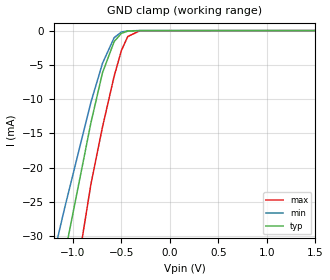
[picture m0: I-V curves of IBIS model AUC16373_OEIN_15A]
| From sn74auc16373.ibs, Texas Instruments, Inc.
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[Model]   AUC16373_OEIN_15A
Model_type  Input
Vinl=0.49
Vinh=1.04
| variable   typ   min   max
C_comp   2.54pF   2.09pF   2.93pF
[Temperature Range]   40   100   -40
| Ambient temperature   25   85   -40
[Voltage range]   1.5   1.4   1.6
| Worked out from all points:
|   GND clamp passes 1 mA (typ) near -0.55 V on its own axis
[GND Clamp]
| AUC16373_OEIN_15A
|   Voltage   I(typ)   I(min)   I(max)
-3.6V     -226.6mA   -190.3mA   -271.8mA
-1.465V   -61.48mA   -49.43mA   -80.77mA
-1.29V    -48.15mA   -38.43mA   -64.9mA
-1.13V    -36.11mA   -28.6mA    -50.37mA
-1.08V    -32.4mA    -25.59mA   -45.83mA
-815mV    -13.48mA   -10.49mA   -22.45mA
-695mV    -6.152mA   -4.773mA   -14.06mA
-575mV    -1.605mA   -1.034mA   -6.664mA
-500mV    -407.2uA   -207.5uA   -2.896mA
-435mV    -83.64uA   -40.42uA   -873uA
-310mV    -2.072uA   -1.331uA   -17.49uA
1.5V      165.9pA    259.7pA    172.1pA
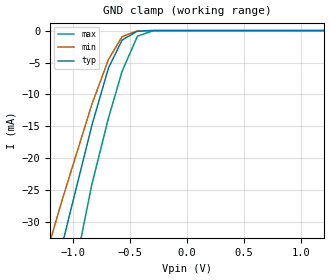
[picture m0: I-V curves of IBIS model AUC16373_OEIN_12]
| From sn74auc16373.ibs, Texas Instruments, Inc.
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[Model]   AUC16373_OEIN_12
Model_type  Input
Vinl=0.385
Vinh=0.845
| variable   typ   min   max
C_comp   2.58pF   2.18pF   2.94pF
[Temperature Range]   40   100   -40
| Ambient temperature   25   85   -40
[Voltage range]   1.2   1.1   1.3
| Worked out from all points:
|   GND clamp passes 1 mA (typ) near -0.55 V on its own axis
[GND Clamp]
| AUC16373_OEIN_12
|   Voltage   I(typ)   I(min)   I(max)
-3.6V     -226.6mA   -190.3mA   -271.8mA
-1.47V    -61.86mA   -49.74mA   -81.22mA
-1.425V   -58.42mA   -46.89mA   -77.15mA
-1.295V   -48.52mA   -38.74mA   -65.35mA
-1.13V    -36.11mA   -28.6mA    -50.37mA
-1.09V    -33.13mA   -26.19mA   -46.74mA
-835mV    -14.83mA   -11.55mA   -24.08mA
-690mV    -5.892mA   -4.567mA   -13.74mA
-570mV    -1.488mA   -943.5uA   -6.381mA
-435mV    -83.64uA   -40.42uA   -873uA
-295mV    -1.276uA   -867.5nA   -9.761uA
1.2V      133.3pA    224.2pA    123.7pA
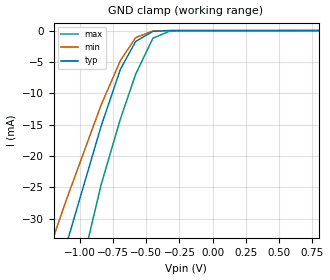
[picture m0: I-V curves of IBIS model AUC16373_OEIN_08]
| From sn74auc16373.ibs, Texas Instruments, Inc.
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[Model]   AUC16373_OEIN_08
Model_type  Input
Vinl=0
Vinh=0.8
| variable   typ   min   max
C_comp   2.61pF   2.27pF   2.93pF
[Temperature Range]   40   100   -40
| Ambient temperature   25   85   -40
[Voltage range]   0.8   0.8   0.8
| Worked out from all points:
|   GND clamp passes 1 mA (typ) near -0.55 V on its own axis
[GND Clamp]
| AUC16373_OEIN_08
|   Voltage   I(typ)   I(min)   I(max)
-3.6V     -226.6mA   -190.3mA   -271.8mA
-1.485V   -63.01mA   -50.7mA    -82.58mA
-1.445V   -59.95mA   -48.16mA   -78.96mA
-1.305V   -49.28mA   -39.36mA   -66.26mA
-1.135V   -36.48mA   -28.9mA    -50.82mA
-1.1V     -33.88mA   -26.79mA   -47.64mA
-840mV    -15.17mA   -11.81mA   -24.5mA
-695mV    -6.152mA   -4.773mA   -14.06mA
-580mV    -1.726mA   -1.13mA    -6.949mA
-450mV    -123.7uA   -59.61uA   -1.212mA
-315mV    -2.431uA   -1.534uA   -21.15uA
800mV     96.17pA    180.2pA    76.88pA
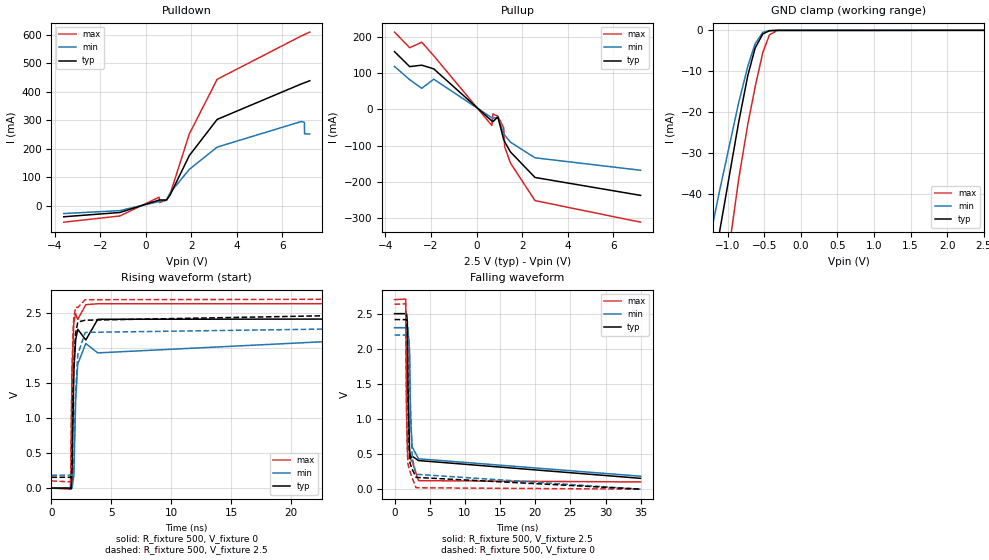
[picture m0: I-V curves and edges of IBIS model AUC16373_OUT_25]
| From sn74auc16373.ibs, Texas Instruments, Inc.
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[Model]   AUC16373_OUT_25
Model_type  3-state
Enable   Active-Low
Vref =   0
Rref =   500
Cref =   30p
Vmeas =   1.25
| variable   typ   min   max
C_comp   5.25pF   4.69pF   5.48pF
| C_pullup   7.79pF   4.63pF   11.98pF
| C_pulldown   6.70pF   4.68pF   15.30pF
| C_tri-state   5.25pF   4.69pF   5.48pF
[Temperature Range]   40   100   -40
| Ambient temperature   25   85   -40
[Voltage range]   2.5   2.3   2.7
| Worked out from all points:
|   slope of the pulldown table from 0 to 0.375 V, typ, clamps not added: 30.7 ohm
|   slope of the pullup table from 0 to 0.375 V, typ, clamps not added: 19 ohm
|   GND clamp passes 1 mA (typ) near -0.53 V on its own axis
|   rising waveform, R_fixture 500, V_fixture 0: 20-80 % time 198ps typ, 278ps min, 143ps max; typ from 0 V to 2.42 V
|   falling waveform, R_fixture 500, V_fixture 2.5: 20-80 % time 246ps typ, 345ps min, 178ps max; typ from 2.5 V to 0.154 V
|   rising waveform, R_fixture 500, V_fixture 2.5: 20-80 % time 201ps typ, 284ps min, 143ps max; typ from 0.154 V to 2.5 V
|   falling waveform, R_fixture 500, V_fixture 0: 20-80 % time 266ps typ, 378ps min, 182ps max; typ from 2.42 V to 0 V
[GND Clamp]
| AUC16373_OUT_25
|   Voltage   I(typ)   I(min)   I(max)
-3.6V     -322.9mA   -271.3mA   -392.8mA
-1.455V   -86.41mA   -69.74mA   -115.3mA
-1.345V   -74.46mA   -59.86mA   -100.9mA
-1.295V   -69.05mA   -55.41mA   -94.31mA
-1.105V   -48.71mA   -38.79mA   -69.37mA
-850mV    -22.51mA   -17.75mA   -36.48mA
-725mV    -11.06mA   -8.768mA   -23.02mA
-625mV    -4.339mA   -3.267mA   -13.84mA
-520mV    -878.8uA   -491uA     -5.429mA
-430mV    -104.5uA   -60.64uA   -1.111mA
-325mV    -4.915uA   -5.536uA   -43.94uA
2.5V      1.045nA    211.8nA    1.502nA
[Pulldown]
| AUC16373_OUT_25
|   Voltage   I(typ)   I(min)   I(max)
-3.6V     -38.75mA   -27.46mA   -57.79mA
-1.14V    -23.79mA   -17.18mA   -36mA
590mV     19.92mA    14.98mA    30.03mA
600mV     20.28mA    15.25mA    11.17mA
910mV     20.16mA    20.33mA    19.24mA
1.07V     37.88mA    45.66mA    41.07mA
1.915V    176.4mA    127.8mA    252.5mA
3.135V    303.2mA    205.9mA    444mA
6.825V    427.7mA    295.8mA    596.2mA
6.965V    431.9mA    293mA      601.3mA
6.97V     432.1mA    252.7mA    601.5mA
7.2V      439mA      251.9mA    609.9mA
[Pullup]
| AUC16373_OUT_25
|   Voltage   I(typ)   I(min)   I(max)
-3.6V     160mA      119mA      214.2mA
-2.935V   118.6mA    82.49mA    170.9mA
-2.405V   122.6mA    58.64mA    186.2mA
-1.88V    112.5mA    83.79mA    148.8mA
670mV     -31.69mA   -22.93mA   -44.2mA
720mV     -33.47mA   -24.18mA   -12.23mA
935mV     -20.74mA   -21.43mA   -18.64mA
1.19V     -83.17mA   -67.47mA   -51.41mA
1.235V    -89.46mA   -71.21mA   -103.5mA
1.49V     -117.6mA   -90.51mA   -148.5mA
2.565V    -188.1mA   -133.7mA   -252.1mA
7.2V      -237.7mA   -168.2mA   -311.9mA
[Ramp]
| AUC16373_OUT_25
| variable   typ   min   max
dV/dt_r   1.46/1.99E-10   1.33/2.81E-10   1.59/1.45E-10
dV/dt_f   1.41/2.48E-10   1.27/3.47E-10   1.56/1.79E-10
R_load = 500
[Rising Waveform]
| AUC16373_OUT_25
R_fixture =   500
C_fixture =   0
L_fixture =   0
V_fixture =   0
V_fixture_min = 0
V_fixture_max = 0
|   Time   V(typ)   V(min)   V(max)
0s        12.33nV    36.82nV    2.005nV
1.585ns   -465.6uV   686.3uV    -15.47mV
1.635ns   -12.82mV   864.7uV    242.2mV
1.715ns   136.4mV    -5.862mV   1.619V
1.875ns   1.678V     178.2mV    2.364V
2.025ns   2.118V     1.253V     2.49V
2.2ns     2.268V     1.772V     2.409V
2.87ns    2.116V     2.065V     2.62V
3.87ns    2.411V     1.931V     2.633V
34.99ns   2.416V     2.195V     2.634V
[Falling Waveform]
| AUC16373_OUT_25
R_fixture =   500
C_fixture =   0
L_fixture =   0
V_fixture =   2.5
V_fixture_min = 2.3
V_fixture_max = 2.7
|   Time   V(typ)   V(min)   V(max)
0s        2.5V       2.3V       2.7V
1.585ns   2.5V       2.3V       2.708V
1.715ns   2.498V     2.3V       1.101V
1.82ns    2.391V     2.299V     644.1mV
1.905ns   1.439V     2.298V     432mV
2.135ns   572.3mV    1.975V     439.6mV
2.275ns   438.4mV    1.042V     426.9mV
2.495ns   469.6mV    605.1mV    396.2mV
3.405ns   407.7mV    433mV      121mV
34.99ns   154.5mV    184.4mV    102.7mV
[Rising Waveform]
| AUC16373_OUT_25
R_fixture =   500
C_fixture =   0
L_fixture =   0
V_fixture =   2.5
V_fixture_min = 2.3
V_fixture_max = 2.7
|   Time   V(typ)   V(min)   V(max)
0s        154.5mV    184.4mV    102.6mV
1.585ns   154.2mV    185mV      88.67mV
1.63ns    144.9mV    185.2mV    300.5mV
1.705ns   261.9mV    181.8mV    1.588V
1.81ns    1.379V     206.7mV    2.255V
1.87ns    1.74V      394.7mV    2.437V
2.02ns    2.212V     1.372V     2.584V
2.205ns   2.372V     1.91V      2.58V
2.825ns   2.398V     2.224V     2.691V
34.99ns   2.5V       2.3V       2.7V
[Falling Waveform]
| AUC16373_OUT_25
R_fixture =   500
C_fixture =   0
L_fixture =   0
V_fixture =   0
V_fixture_min = 0
V_fixture_max = 0
|   Time   V(typ)   V(min)   V(max)
0s        2.416V     2.195V     2.634V
1.585ns   2.415V     2.195V     2.64V
1.71ns    2.413V     2.195V     1.095V
1.82ns    2.295V     2.194V     565.5mV
1.89ns    1.522V     2.193V     367.9mV
2.075ns   596.8mV    2.11V      294mV
2.2ns     369.3mV    1.33V      253.3mV
2.525ns   281.2mV    437.4mV    155.7mV
3.07ns    167.6mV    211.8mV    20.01mV
34.99ns   28.01uV    546.6nV    12.98uV
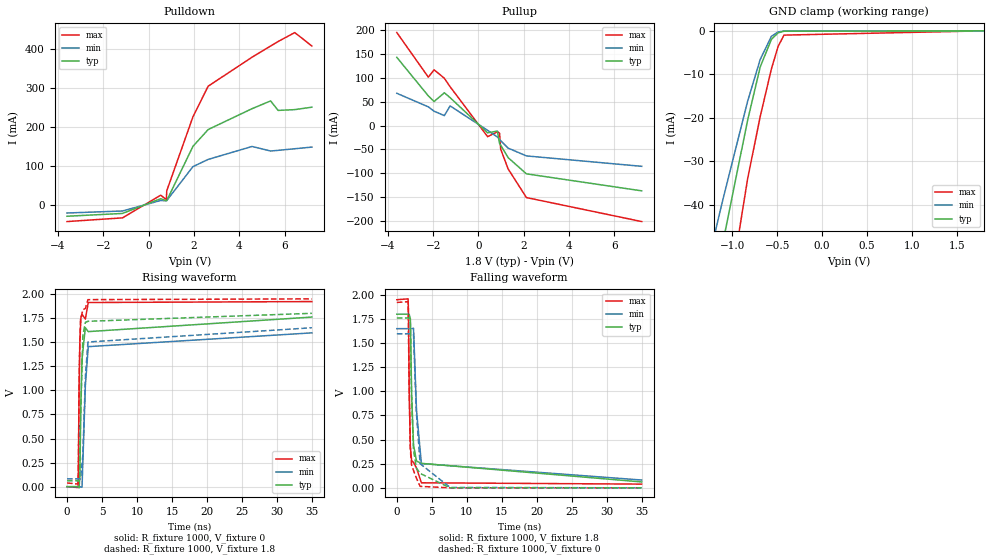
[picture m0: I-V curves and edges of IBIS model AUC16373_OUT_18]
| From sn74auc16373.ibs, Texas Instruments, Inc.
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[Model]   AUC16373_OUT_18
Model_type  3-state
Enable   Active-Low
Vref =   0
Rref =   1000
Cref =   30p
Vmeas =   0.9
| variable   typ   min   max
C_comp   5.46pF   4.89pF   5.67pF
| C_pullup   6.29pF   0.99pF   11.78pF
| C_pulldown   6.09pF   1.85pF   13.80pF
| C_tri-state   5.46pF   4.89pF   5.67pF
[Temperature Range]   40   100   -40
| Ambient temperature   25   85   -40
[Voltage range]   1.8   1.65   1.95
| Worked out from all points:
|   slope of the pulldown table from 0 to 0.27 V, typ, clamps not added: 34.2 ohm
|   slope of the pullup table from 0 to 0.27 V, typ, clamps not added: 24.9 ohm
|   GND clamp passes 1 mA (typ) near -0.53 V on its own axis
|   rising waveform, R_fixture 1000, V_fixture 0: 20-80 % time 306ps typ, 479ps min, 198ps max; typ from 0 V to 1.76 V
|   falling waveform, R_fixture 1000, V_fixture 1.8: 20-80 % time 400ps typ, 627ps min, 239ps max; typ from 1.8 V to 0.061 V
|   rising waveform, R_fixture 1000, V_fixture 1.8: 20-80 % time 304ps typ, 475ps min, 196ps max; typ from 0.061 V to 1.8 V
|   falling waveform, R_fixture 1000, V_fixture 0: 20-80 % time 401ps typ, 630ps min, 238ps max; typ from 1.76 V to 0 V
[GND Clamp]
| AUC16373_OUT_18
|   Voltage   I(typ)   I(min)   I(max)
-3.6V     -322.9mA   -271.3mA   -392.8mA
-1.48V    -89.14mA   -71.99mA   -118.6mA
-1.435V   -84.24mA   -67.93mA   -112.7mA
-1.3V     -69.59mA   -55.85mA   -94.97mA
-1.15V    -53.49mA   -42.68mA   -75.27mA
-1.1V     -48.18mA   -38.36mA   -68.71mA
-830mV    -20.57mA   -16.22mA   -34.06mA
-690mV    -8.335mA   -6.605mA   -19.75mA
-565mV    -1.951mA   -1.255mA   -8.764mA
-490mV    -463.9uA   -245.9uA   -3.576mA
-425mV    -91.38uA   -54.15uA   -985.3uA
1.8V      674.7pA    45.17nA    747.9pA
[Pulldown]
| AUC16373_OUT_18
|   Voltage   I(typ)   I(min)   I(max)
-3.6V     -28.49mA   -20.22mA   -42.08mA
-1.155V   -21.32mA   -15.05mA   -32.66mA
530mV     16.28mA    11.83mA    25.26mA
780mV     11.06mA    10.81mA    14.1mA
800mV     11.7mA     11.72mA    36.72mA
1.955V    150.3mA    98.42mA    225.9mA
2.625V    193.2mA    116.8mA    304mA
4.56V     246.5mA    149.9mA    378.1mA
5.38V     266.4mA    138.3mA    406.9mA
5.71V     242.1mA    140mA      418.2mA
6.445V    244.1mA    144.1mA    441.1mA
7.2V      250.4mA    148.3mA    406.7mA
[Pullup]
| AUC16373_OUT_18
|   Voltage   I(typ)   I(min)   I(max)
-3.6V     143.4mA    67.81mA    195.5mA
-2.21V    62.22mA    39.25mA    101.7mA
-1.955V   50.53mA    30.07mA    117.2mA
-1.505V   68.89mA    20.87mA    99.46mA
-1.25V    58.62mA    41.27mA    81.57mA
405mV     -15.38mA   -10.2mA    -23.47mA
835mV     -11.64mA   -24.19mA   -13.09mA
930mV     -37.45mA   -29.05mA   -16.21mA
980mV     -41.44mA   -31.73mA   -49.64mA
1.31V     -67.6mA    -47.58mA   -91.39mA
2.115V    -101.6mA   -63.91mA   -151.5mA
7.2V      -137.4mA   -85.82mA   -202mA
[Ramp]
| AUC16373_OUT_18
| variable   typ   min   max
dV/dt_r   1.07/3.10E-10   0.97/4.87E-10   1.16/1.99E-10
dV/dt_f   1.05/4.02E-10   0.95/6.30E-10   1.15/2.41E-10
R_load = 1000
[Rising Waveform]
| AUC16373_OUT_18
R_fixture =   1000
C_fixture =   0
L_fixture =   0
V_fixture =   0
V_fixture_min = 0
V_fixture_max = 0
|   Time   V(typ)   V(min)   V(max)
0s        9.675nV    33.63nV    1.209nV
1.575ns   554.8uV    24.29uV    -9.009mV
1.62ns    796.3uV    56.73uV    113.6mV
1.725ns   -12.08mV   182.5uV    1.018V
1.835ns   108mV      1.353mV    1.498V
1.98ns    865.2mV    -5.302mV   1.752V
2.145ns   1.329V     -3.297mV   1.79V
2.62ns    1.651V     1.049V     1.74V
3.035ns   1.61V      1.454V     1.912V
34.99ns   1.761V     1.597V     1.922V
[Falling Waveform]
| AUC16373_OUT_18
R_fixture =   1000
C_fixture =   0
L_fixture =   0
V_fixture =   1.8
V_fixture_min = 1.65
V_fixture_max = 1.95
|   Time   V(typ)   V(min)   V(max)
0s        1.8V       1.65V      1.95V
1.61ns    1.8V       1.65V      1.959V
1.665ns   1.8V       1.65V      1.838V
1.77ns    1.798V     1.65V      1.003V
1.935ns   1.752V     1.65V      423.6mV
2.115ns   962.5mV    1.65V      281.6mV
2.385ns   443.9mV    1.655V     264.3mV
2.815ns   278.2mV    798.9mV    204.5mV
3.51ns    253.9mV    251.7mV    52.38mV
34.99ns   61.08mV    81.02mV    38.7mV
[Rising Waveform]
| AUC16373_OUT_18
R_fixture =   1000
C_fixture =   0
L_fixture =   0
V_fixture =   1.8
V_fixture_min = 1.65
V_fixture_max = 1.95
|   Time   V(typ)   V(min)   V(max)
0s        61.05mV    81.01mV    38.68mV
1.57ns    61.53mV    81.03mV    27.73mV
1.62ns    61.82mV    81.06mV    167.1mV
1.705ns   54.68mV    81.13mV    929.6mV
1.8ns     84.7mV     81.83mV    1.417V
1.925ns   686.5mV    80.95mV    1.734V
2.27ns    1.574V     336.2mV    1.837V
2.625ns   1.706V     1.144V     1.85V
2.99ns    1.717V     1.502V     1.942V
34.99ns   1.8V       1.65V      1.95V
[Falling Waveform]
| AUC16373_OUT_18
R_fixture =   1000
C_fixture =   0
L_fixture =   0
V_fixture =   0
V_fixture_min = 0
V_fixture_max = 0
|   Time   V(typ)   V(min)   V(max)
0s        1.761V     1.597V     1.922V
1.61ns    1.761V     1.597V     1.93V
1.765ns   1.759V     1.597V     1.008V
1.93ns    1.716V     1.597V     395.4mV
2.1ns     974.7mV    1.597V     236.6mV
2.38ns    393.7mV    1.596V     181mV
2.8ns     204.6mV    768.9mV    100.5mV
3.33ns    149.6mV    250mV      15.44mV
7.615ns   329.2uV    4.425mV    113.2uV
34.99ns   34.64uV    2.32uV     14.99uV
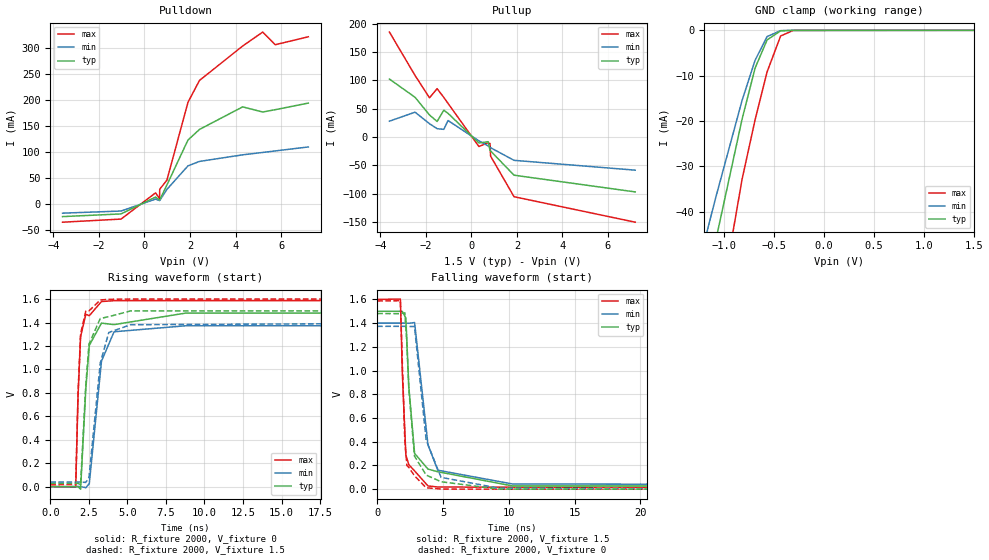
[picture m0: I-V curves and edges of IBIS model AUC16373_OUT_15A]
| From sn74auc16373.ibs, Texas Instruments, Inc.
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[Model]   AUC16373_OUT_15A
Model_type  3-state
Enable   Active-Low
Vref =   0
Rref =   2000
Cref =   15p
Vmeas =   0.75
| variable   typ   min   max
C_comp   5.56pF   5.00pF   5.81pF
| C_pullup   4.92pF   0.36pF   12.47pF
| C_pulldown   6.29pF   5.37pF   9.88pF
| C_tri-state   5.56pF   5.00pF   5.81pF
[Temperature Range]   40   100   -40
| Ambient temperature   25   85   -40
[Voltage range]   1.5   1.4   1.6
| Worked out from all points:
|   slope of the pulldown table from 0 to 0.225 V, typ, clamps not added: 37.2 ohm
|   slope of the pullup table from 0 to 0.225 V, typ, clamps not added: 30 ohm
|   GND clamp passes 1 mA (typ) near -0.53 V on its own axis
|   rising waveform, R_fixture 2000, V_fixture 0: 20-80 % time 406ps typ, 638ps min, 248ps max; typ from 0 V to 1.48 V
|   falling waveform, R_fixture 2000, V_fixture 1.5: 20-80 % time 546ps typ, 882ps min, 307ps max; typ from 1.5 V to 0.027 V
|   rising waveform, R_fixture 2000, V_fixture 1.5: 20-80 % time 402ps typ, 633ps min, 245ps max; typ from 0.027 V to 1.5 V
|   falling waveform, R_fixture 2000, V_fixture 0: 20-80 % time 542ps typ, 875ps min, 304ps max; typ from 1.48 V to 0 V
[GND Clamp]
| AUC16373_OUT_15A
|   Voltage   I(typ)   I(min)   I(max)
-3.6V     -322.9mA   -271.3mA   -392.8mA
-1.475V   -88.59mA   -71.54mA   -117.9mA
-1.34V    -73.92mA   -59.41mA   -100.2mA
-1.3V     -69.59mA   -55.85mA   -94.97mA
-1.135V   -51.9mA    -41.38mA   -73.31mA
-1.085V   -46.6mA    -37.08mA   -66.75mA
-820mV    -19.61mA   -15.47mA   -32.88mA
-690mV    -8.335mA   -6.605mA   -19.75mA
-570mV    -2.107mA   -1.378mA   -9.166mA
-435mV    -119.4uA   -67.96uA   -1.249mA
-310mV    -3.104uA   -3.774uA   -25uA
1.5V      550.3pA    9.378nA    545.2pA
[Pulldown]
| AUC16373_OUT_15A
|   Voltage   I(typ)   I(min)   I(max)
-3.6V     -23.87mA   -17.26mA   -34.61mA
-1.03V    -18.71mA   -13.15mA   -28.63mA
485mV     13.68mA    9.737mA    21.72mA
660mV     8.179mA    6.953mA    10.96mA
670mV     8.319mA    7.1mA      28.79mA
985mV     36.88mA    28.41mA    46.12mA
1.91V     123.2mA    73.57mA    195.6mA
2.415V    143.6mA    82.17mA    237.7mA
4.315V    187mA      94.84mA    304mA
5.195V    177.1mA    99.4mA     330.7mA
5.745V    181.6mA    102.3mA    306.4mA
7.2V      194.3mA    110mA      321.7mA
[Pullup]
| AUC16373_OUT_15A
|   Voltage   I(typ)   I(min)   I(max)
-3.6V     102.1mA    27.92mA    184.9mA
-2.475V   70.01mA    43.77mA    108.5mA
-1.84V    38.84mA    23.47mA    69.11mA
-1.505V   27.39mA    14.66mA    85.19mA
-1.21V    47.39mA    13.5mA     69.72mA
-1.025V   41.71mA    29.01mA    59.25mA
330mV     -10.46mA   -6.758mA   -16.68mA
740mV     -8.272mA   -15.76mA   -10.25mA
820mV     -23.65mA   -18mA      -11.49mA
845mV     -24.61mA   -18.86mA   -33.67mA
1.875V    -67.28mA   -41.09mA   -105.2mA
7.2V      -96.75mA   -58.41mA   -150.1mA
[Ramp]
| AUC16373_OUT_15A
| variable   typ   min   max
dV/dt_r   0.90/4.08E-10   0.83/6.50E-10   0.96/2.49E-10
dV/dt_f   0.89/5.49E-10   0.82/8.93E-10   0.95/3.07E-10
R_load = 2000
[Rising Waveform]
| AUC16373_OUT_15A
R_fixture =   2000
C_fixture =   0
L_fixture =   0
V_fixture =   0
V_fixture_min = 0
V_fixture_max = 0
|   Time   V(typ)   V(min)   V(max)
0s        8.895nV    33.88nV    950.2pV
1.65ns    8.033uV    38.9uV     -4.678mV
1.8ns     373.4uV    261.9uV    773.5mV
1.965ns   -21.9mV    621.6uV    1.279V
2.305ns   834.7mV    -9.422mV   1.47V
2.53ns    1.205V     25.26mV    1.458V
3.32ns    1.395V     1.07V      1.579V
4.135ns   1.382V     1.321V     1.586V
8.765ns   1.48V      1.372V     1.587V
34.99ns   1.481V     1.373V     1.587V
[Falling Waveform]
| AUC16373_OUT_15A
R_fixture =   2000
C_fixture =   0
L_fixture =   0
V_fixture =   1.5
V_fixture_min = 1.4
V_fixture_max = 1.6
|   Time   V(typ)   V(min)   V(max)
0s        1.5V       1.4V       1.6V
1.765ns   1.5V       1.4V       1.603V
1.91ns    1.499V     1.4V       988.1mV
2.18ns    1.444V     1.4V       289mV
2.405ns   863.5mV    1.399V     206.4mV
2.845ns   301.2mV    1.405V     154mV
3.86ns    169.3mV    374.8mV    27.48mV
4.605ns   147mV      160mV      18.27mV
10.27ns   27.45mV    44.07mV    16.49mV
34.99ns   27.21mV    38.76mV    16.42mV
[Rising Waveform]
| AUC16373_OUT_15A
R_fixture =   2000
C_fixture =   0
L_fixture =   0
V_fixture =   1.5
V_fixture_min = 1.4
V_fixture_max = 1.6
|   Time   V(typ)   V(min)   V(max)
0s        27.17mV    38.75mV    16.4mV
1.65ns    27.18mV    38.79mV    17.02mV
1.8ns     27.59mV    38.98mV    799.5mV
1.965ns   14.56mV    39.28mV    1.302V
2.3ns     861.5mV    35.58mV    1.496V
2.51ns    1.216V     78.12mV    1.499V
3.24ns    1.434V     1.054V     1.592V
3.795ns   1.45V      1.315V     1.598V
5.21ns    1.499V     1.381V     1.6V
34.99ns   1.5V       1.4V       1.6V
[Falling Waveform]
| AUC16373_OUT_15A
R_fixture =   2000
C_fixture =   0
L_fixture =   0
V_fixture =   0
V_fixture_min = 0
V_fixture_max = 0
|   Time   V(typ)   V(min)   V(max)
0s        1.481V     1.373V     1.587V
1.765ns   1.48V      1.373V     1.589V
2.1ns     1.487V     1.373V     414.7mV
2.255ns   1.242V     1.372V     201.1mV
2.41ns    837.6mV    1.371V     182.5mV
2.835ns   278.8mV    1.372V     113.4mV
3.725ns   118.7mV    412.9mV    11.7mV
4.855ns   62.72mV    99.58mV    1.01mV
9.25ns    318.7uV    8.392mV    103uV
34.99ns   39.77uV    4.299uV    16.51uV
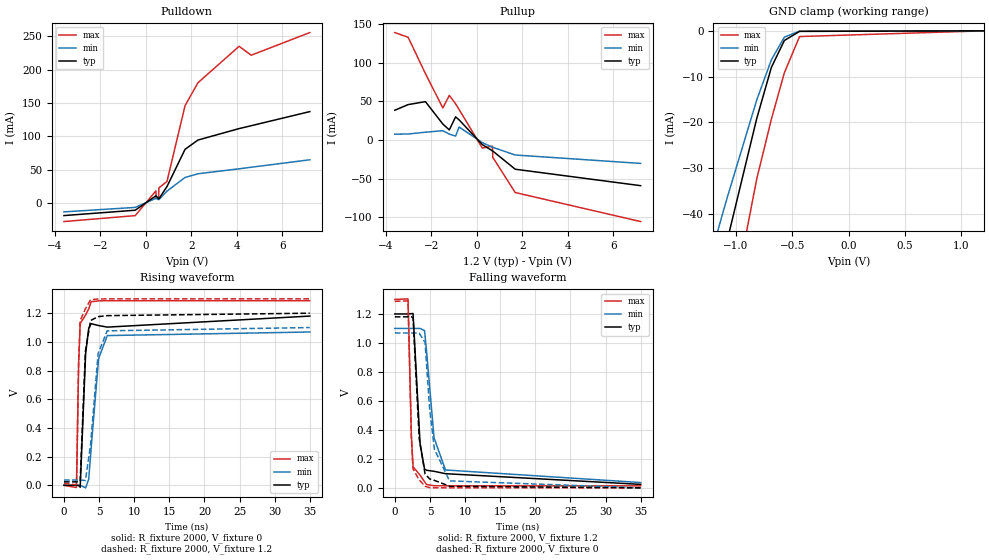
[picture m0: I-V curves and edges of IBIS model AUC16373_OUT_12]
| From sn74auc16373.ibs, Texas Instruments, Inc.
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[Model]   AUC16373_OUT_12
Model_type  3-state
Enable   Active-Low
Vref =   0
Rref =   2000
Cref =   15p
Vmeas =   0.6
| variable   typ   min   max
C_comp   5.67pF   5.13pF   5.90pF
| C_pullup   4.94pF   0.61pF   9.78pF
| C_pulldown   6.25pF   5.49pF   7.45pF
| C_tri-state   5.67pF   5.13pF   5.90pF
[Temperature Range]   40   100   -40
| Ambient temperature   25   85   -40
[Voltage range]   1.2   1.1   1.3
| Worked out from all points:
|   slope of the pulldown table from 0 to 0.18 V, typ, clamps not added: 42.1 ohm
|   slope of the pullup table from 0 to 0.18 V, typ, clamps not added: 38.3 ohm
|   GND clamp passes 1 mA (typ) near -0.53 V on its own axis
|   rising waveform, R_fixture 2000, V_fixture 0: 20-80 % time 583ps typ, 1.04ns min, 320ps max; typ from 0 V to 1.18 V
|   falling waveform, R_fixture 2000, V_fixture 1.2: 20-80 % time 855ps typ, 1.39ns min, 422ps max; typ from 1.2 V to 0.024 V
|   rising waveform, R_fixture 2000, V_fixture 1.2: 20-80 % time 575ps typ, 1.03ns min, 314ps max; typ from 0.024 V to 1.2 V
|   falling waveform, R_fixture 2000, V_fixture 0: 20-80 % time 842ps typ, 1.32ns min, 416ps max; typ from 1.18 V to 0 V
[GND Clamp]
| AUC16373_OUT_12
|   Voltage   I(typ)   I(min)   I(max)
-3.6V     -322.9mA   -271.3mA   -392.8mA
-1.47V    -88.05mA   -71.09mA   -117.3mA
-1.425V   -83.15mA   -67.03mA   -111.4mA
-1.3V     -69.59mA   -55.85mA   -94.97mA
-1.26V    -65.27mA   -52.31mA   -89.72mA
-1.11V    -49.24mA   -39.22mA   -70.03mA
-1.075V   -45.55mA   -36.22mA   -65.44mA
-815mV    -19.13mA   -15.09mA   -32.31mA
-685mV    -7.975mA   -6.314mA   -19.28mA
-570mV    -2.107mA   -1.378mA   -9.166mA
-435mV    -119.4uA   -67.96uA   -1.249mA
1.2V      442.5pA    9.259nA    389.9pA
[Pulldown]
| AUC16373_OUT_12
|   Voltage   I(typ)   I(min)   I(max)
-3.6V     -19.18mA   -13.63mA   -28.17mA
-470mV    -11.13mA   -6.91mA    -19.23mA
440mV     10.48mA    6.706mA    17.92mA
445mV     10.59mA    6.769mA    6.318mA
560mV     5.857mA    4.698mA    8.209mA
570mV     5.97mA     4.786mA    22.41mA
925mV     24.38mA    17.54mA    32.09mA
1.72V     80.36mA    38.11mA    146mA
2.285V    94.25mA    43.63mA    180.3mA
4.095V    111.5mA    51.07mA    235.1mA
4.625V    115.8mA    53.41mA    221.7mA
7.2V      137mA      64.62mA    255.7mA
[Pullup]
| AUC16373_OUT_12
|   Voltage   I(typ)   I(min)   I(max)
-3.6V     38.61mA    7.555mA    139.2mA
-3.015V   45.91mA    7.851mA    133.1mA
-2.255V   49.73mA    10.14mA    86.01mA
-1.49V    20.68mA    12.09mA    41.55mA
-1.205V   13.08mA    7.704mA    57.86mA
-930mV    30.05mA    5.088mA    46.93mA
-775mV    26.1mA     16.83mA    39.5mA
245mV     -5.916mA   -3.381mA   -10.43mA
690mV     -14.05mA   -9.319mA   -7.997mA
705mV     -14.25mA   -9.473mA   -22.45mA
1.69V     -37.81mA   -19.38mA   -68.01mA
7.2V      -59.11mA   -30.28mA   -105.6mA
[Ramp]
| AUC16373_OUT_12
| variable   typ   min   max
dV/dt_r   0.72/5.96E-10   0.65/1.06E-09   0.78/3.23E-10
dV/dt_f   0.71/8.67E-10   0.64/1.43E-09   0.77/4.24E-10
R_load = 2000
[Rising Waveform]
| AUC16373_OUT_12
R_fixture =   2000
C_fixture =   0
L_fixture =   0
V_fixture =   0
V_fixture_min = 0
V_fixture_max = 0
|   Time   V(typ)   V(min)   V(max)
0s        8.336nV    36nV       765.5pV
1.77ns    140.6uV    -1.439uV   -15.28mV
2.085ns   -1.371mV   128.8uV    841.3mV
2.305ns   -13.39mV   301.3uV    1.128V
3.08ns    919.1mV    -17.75mV   1.188V
3.52ns    1.094V     42.93mV    1.229V
3.865ns   1.127V     258.3mV    1.28V
4.925ns   1.114V     883.6mV    1.286V
6.17ns    1.103V     1.044V     1.287V
34.99ns   1.18V      1.069V     1.287V
[Falling Waveform]
| AUC16373_OUT_12
R_fixture =   2000
C_fixture =   0
L_fixture =   0
V_fixture =   1.2
V_fixture_min = 1.1
V_fixture_max = 1.3
|   Time   V(typ)   V(min)   V(max)
0s        1.2V       1.1V       1.3V
1.88ns    1.2V       1.1V       1.304V
2.355ns   1.202V     1.1V       366.1mV
2.595ns   1.203V     1.1V       145.6mV
3.595ns   304.3mV    1.1V       87.5mV
4.23ns    129.6mV    1.085V     42.1mV
4.52ns    121.3mV    941.7mV    23.25mV
5.585ns   114.2mV    345.2mV    14.69mV
7.21ns    97.74mV    123.4mV    14.05mV
34.99ns   24.03mV    36.64mV    13.88mV
[Rising Waveform]
| AUC16373_OUT_12
R_fixture =   2000
C_fixture =   0
L_fixture =   0
V_fixture =   1.2
V_fixture_min = 1.1
V_fixture_max = 1.3
|   Time   V(typ)   V(min)   V(max)
0s        23.98mV    36.61mV    13.86mV
1.77ns    24.1mV     36.61mV    3.599mV
1.82ns    24.16mV    36.61mV    72.51mV
2.08ns    23.65mV    36.68mV    859.5mV
2.305ns   26.1mV     36.78mV    1.149V
3.05ns    935.8mV    32.98mV    1.23V
3.78ns    1.149V     281.1mV    1.294V
4.855ns   1.176V     918.2mV    1.299V
6.15ns    1.183V     1.077V     1.3V
34.99ns   1.2V       1.1V       1.3V
[Falling Waveform]
| AUC16373_OUT_12
R_fixture =   2000
C_fixture =   0
L_fixture =   0
V_fixture =   0
V_fixture_min = 0
V_fixture_max = 0
|   Time   V(typ)   V(min)   V(max)
0s        1.18V      1.069V     1.287V
1.88ns    1.18V      1.069V     1.29V
2.355ns   1.18V      1.069V     340.6mV
2.595ns   1.175V     1.069V     130.3mV
3.47ns    340.6mV    1.067V     54.88mV
4.305ns   96.05mV    1.003V     10.78mV
4.955ns   61.66mV    544.4mV    1.605mV
5.64ns    51.53mV    266.1mV    620uV
7.795ns   10.93mV    47.95mV    160.8uV
34.99ns   48.71uV    14.57uV    18.44uV
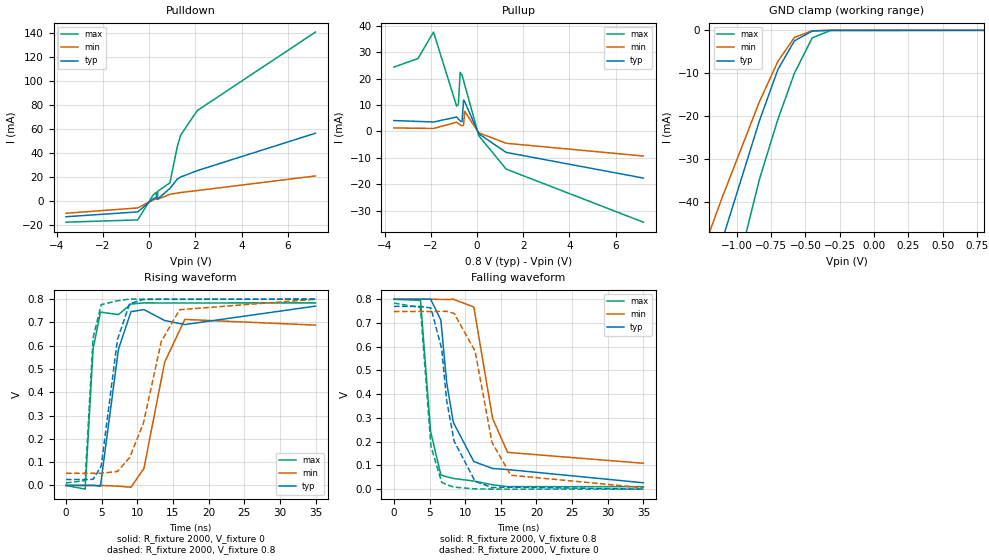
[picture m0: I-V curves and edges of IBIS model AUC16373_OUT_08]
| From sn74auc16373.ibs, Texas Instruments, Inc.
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[Model]   AUC16373_OUT_08
Model_type  3-state
Enable   Active-Low
Vref =   0
Rref =   2000
Cref =   15p
Vmeas =   0.4
| variable   typ   min   max
C_comp   5.77pF   5.27pF   6.02pF
| C_pullup   5.89pF   1.41pF   8.24pF
| C_pulldown   6.39pF   5.81pF   6.83pF
| C_tri-state   5.77pF   5.27pF   6.02pF
[Temperature Range]   40   100   -40
| Ambient temperature   25   85   -40
[Voltage range]   0.8   0.8   0.8
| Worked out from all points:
|   slope of the pulldown table from 0 to 0.12 V, typ, clamps not added: 77.5 ohm
|   slope of the pullup table from 0 to 0.12 V, typ, clamps not added: 92.7 ohm
|   GND clamp passes 1 mA (typ) near -0.53 V on its own axis
|   rising waveform, R_fixture 2000, V_fixture 0: 20-80 % time 1.85ns typ, 2.59ns min, 923ps max; typ from 0 V to 0.77 V
|   falling waveform, R_fixture 2000, V_fixture 0.8: 20-80 % time 2.69ns typ, 2.33ns min, 1.38ns max; typ from 0.8 V to 0.027 V
|   rising waveform, R_fixture 2000, V_fixture 0.8: 20-80 % time 1.88ns typ, 3.64ns min, 881ps max; typ from 0.025 V to 0.8 V
|   falling waveform, R_fixture 2000, V_fixture 0: 20-80 % time 2.3ns typ, 3.01ns min, 1.25ns max; typ from 0.77 V to 0 V
[GND Clamp]
| AUC16373_OUT_08
|   Voltage   I(typ)   I(min)   I(max)
-3.6V     -322.9mA   -271.3mA   -392.8mA
-1.495V   -90.78mA   -73.35mA   -120.5mA
-1.455V   -86.41mA   -69.74mA   -115.3mA
-1.31V    -70.67mA   -56.74mA   -96.28mA
-1.14V    -52.43mA   -41.81mA   -73.96mA
-1.1V     -48.18mA   -38.36mA   -68.71mA
-835mV    -21.05mA   -16.6mA    -34.66mA
-700mV    -9.08mA    -7.201mA   -20.67mA
-580mV    -2.442mA   -1.648mA   -9.983mA
-450mV    -176.5uA   -96.06uA   -1.735mA
-315mV    -3.617uA   -4.295uA   -30.24uA
800mV     320.2pA    582.4pA    244.4pA
[Pulldown]
| AUC16373_OUT_08
|   Voltage   I(typ)   I(min)   I(max)
-3.6V     -12.84mA   -9.953mA   -17.38mA
-495mV    -8.803mA   -5.523mA   -15.47mA
175mV     2.059mA    1.185mA    5.31mA
310mV     3.174mA    2.053mA    7.502mA
315mV     3.217mA    2.087mA    2.47mA
365mV     1.856mA    1.796mA    2.807mA
370mV     1.894mA    1.829mA    8.27mA
900mV     10.72mA    5.829mA    15.4mA
1.215V    18.4mA     6.852mA    45.18mA
1.365V    20.2mA     7.318mA    55.07mA
2.085V    25.54mA    8.939mA    75.52mA
7.2V      56.65mA    21.1mA     140.8mA
[Pullup]
| AUC16373_OUT_08
|   Voltage   I(typ)   I(min)   I(max)
-3.6V     4.13mA     1.333mA    24.36mA
-2.56V    3.817mA    1.227mA    27.6mA
-1.885V   3.587mA    1.149mA    37.6mA
-885mV    5.478mA    3.491mA    9.6mA
-810mV    4.708mA    3.016mA    10.3mA
-730mV    3.982mA    2.544mA    22.37mA
-650mV    3.702mA    2.149mA    21.3mA
-585mV    11.85mA    2.417mA    19.32mA
-535mV    11.24mA    7.608mA    17.64mA
75mV      -881.4uA   -518.8uA   -1.613mA
1.26V     -7.908mA   -4.45mA    -14.23mA
7.2V      -17.63mA   -9.285mA   -34.31mA
[Ramp]
| AUC16373_OUT_08
| variable   typ   min   max
dV/dt_r   0.47/1.89E-09   0.46/3.10E-09   0.48/9.52E-10
dV/dt_f   0.47/2.73E-09   0.42/2.40E-09   0.48/1.40E-09
R_load = 2000
[Rising Waveform]
| AUC16373_OUT_08
R_fixture =   2000
C_fixture =   0
L_fixture =   0
V_fixture =   0
V_fixture_min = 0
V_fixture_max = 0
|   Time   V(typ)   V(min)   V(max)
0s        10.26nV    58.84nV    576.2pV
2.69ns    -27.02uV   -11.25uV   -16.01mV
3.8ns     129.5uV    -7.482uV   586.6mV
4.83ns    -3.153mV   -37.87uV   744.1mV
7.36ns    585.3mV    -3.175mV   733.7mV
9.115ns   746.1mV    -7.872mV   778.9mV
10.93ns   755mV      73.03mV    783.8mV
13.84ns   708.2mV    529.3mV    783.5mV
16.66ns   690.7mV    712.7mV    783.6mV
34.99ns   769.9mV    688.3mV    783.7mV
[Falling Waveform]
| AUC16373_OUT_08
R_fixture =   2000
C_fixture =   0
L_fixture =   0
V_fixture =   0.8
V_fixture_min = 0.8
V_fixture_max = 0.8
|   Time   V(typ)   V(min)   V(max)
0s        800mV      800mV      800mV
3.73ns    800mV      800mV      795.3mV
5.145ns   800.8mV    800mV      243.4mV
6.585ns   712.3mV    799.4mV    60.26mV
7.395ns   450.6mV    798.8mV    52.21mV
8.33ns    281.2mV    799.9mV    45.18mV
11.21ns   116.3mV    767.3mV    34.2mV
13.85ns   87.08mV    296.9mV    18.41mV
15.94ns   82.74mV    155mV      10.68mV
34.99ns   26.94mV    109.1mV    10.63mV
[Rising Waveform]
| AUC16373_OUT_08
R_fixture =   2000
C_fixture =   0
L_fixture =   0
V_fixture =   0.8
V_fixture_min = 0.8
V_fixture_max = 0.8
|   Time   V(typ)   V(min)   V(max)
0s        25.46mV    51.93mV    10.6mV
2.68ns    25.45mV    51.94mV    21.04mV
3.805ns   26.5mV     51.95mV    634.7mV
4.94ns    83.2mV     51.98mV    776.2mV
7.22ns    626.7mV    60.11mV    792.8mV
8.92ns    780.4mV    119.4mV    800.2mV
10.86ns   798.1mV    267.1mV    799.8mV
13.36ns   799.4mV    617.5mV    799.8mV
15.94ns   798.9mV    754.4mV    799.9mV
34.99ns   799.9mV    799.4mV    800mV
[Falling Waveform]
| AUC16373_OUT_08
R_fixture =   2000
C_fixture =   0
L_fixture =   0
V_fixture =   0
V_fixture_min = 0
V_fixture_max = 0
|   Time   V(typ)   V(min)   V(max)
0s        770mV      748.6mV    783.8mV
3.715ns   770mV      748.6mV    765.2mV
5.195ns   762.9mV    748.6mV    180.2mV
6.7ns     591.3mV    748.9mV    28.75mV
7.41ns    371.4mV    749.2mV    18.67mV
8.445ns   202mV      740.3mV    8.682mV
11.39ns   32.92mV    581.1mV    1.262mV
13.76ns   6.693mV    196.8mV    300.7uV
16.39ns   8.443mV    58.88mV    100.7uV
34.99ns   157.2uV    5.851mV    29.31uV
